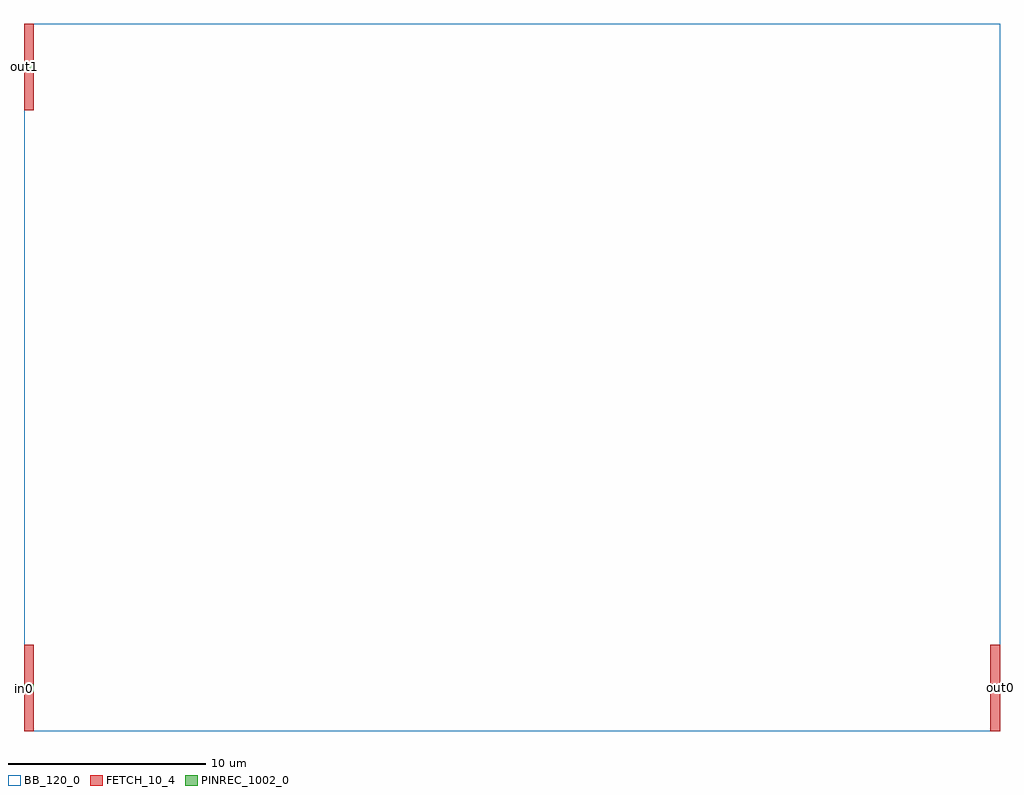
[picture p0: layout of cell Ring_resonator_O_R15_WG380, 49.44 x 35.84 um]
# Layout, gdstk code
import gdstk
lib = gdstk.Library(unit=1e-6, precision=1e-09)
def R(c, l, rs):  # rectangles x0, y0, x1, y1
    for r in rs: c.add(gdstk.rectangle(r[:2], r[2:], *l))
FETCH_10_4 = (10, 4)
BB_120_0 = (120, 0)
PINREC_1002_0 = (1002, 0)

ring_resonator_o_r15_wg3 = lib.new_cell('Ring_resonator_O_R15_WG380')
R(ring_resonator_o_r15_wg3, FETCH_10_4, [(0,0,0.5,2), (48.938,0,49.438,2), (0,2.38,0.5,4.38), (48.938,2.38,49.438,4.38), (0,31.46,0.5,33.46), (0,33.84,0.5,35.84)])
R(ring_resonator_o_r15_wg3, BB_120_0, [(0,0,49.438,35.84)])
R(ring_resonator_o_r15_wg3, PINREC_1002_0, [(0,2,0.5,2.38), (48.938,2,49.438,2.38), (0,33.46,0.5,33.84)])
ring_resonator_o_r15_wg3.add(gdstk.Label('out0', (49.438,2.202), layer=1000, texttype=0))
ring_resonator_o_r15_wg3.add(gdstk.Label('in0', (0,2.192), layer=1000, texttype=0))
ring_resonator_o_r15_wg3.add(gdstk.Label('out1', (0,33.67), layer=1000, texttype=0))

lib.write_gds('Ring_resonator_O_R15_WG380.gds')
